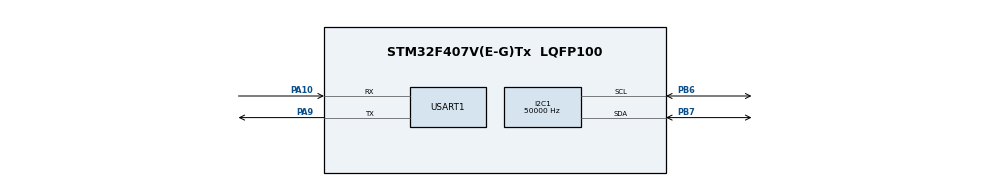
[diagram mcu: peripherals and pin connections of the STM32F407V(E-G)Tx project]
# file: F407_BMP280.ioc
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I2C1.ClockSpeed=50000
I2C1.I2C_Mode=I2C_Fast
Mcu.Family=STM32F4
Mcu.Name=STM32F407V(E-G)Tx
Mcu.Package=LQFP100
NVIC.I2C1_ER_IRQn=true\:0\:0\:false\:false\:true\:true\:true\:true
NVIC.I2C1_EV_IRQn=true\:0\:0\:false\:false\:true\:true\:true\:true
NVIC.PriorityGroup=NVIC_PRIORITYGROUP_4
NVIC.USART1_IRQn=true\:0\:0\:false\:false\:true\:true\:true\:true
PA10.Mode=Asynchronous
PA10.Signal=USART1_RX
PA9.Mode=Asynchronous
PA9.Signal=USART1_TX
PB6.Mode=I2C
PB6.Signal=I2C1_SCL
PB7.Mode=I2C
PB7.Signal=I2C1_SDA
PH0-OSC_IN.Mode=HSE-External-Oscillator
PH0-OSC_IN.Signal=RCC_OSC_IN
PH1-OSC_OUT.Mode=HSE-External-Oscillator
PH1-OSC_OUT.Signal=RCC_OSC_OUT
ProjectManager.HeapSize=0x200
ProjectManager.StackSize=0x400
ProjectManager.TargetToolchain=STM32CubeIDE
RCC.48MHZClocksFreq_Value=36000000
RCC.AHBFreq_Value=72000000
RCC.APB1CLKDivider=RCC_HCLK_DIV2
RCC.APB1Freq_Value=36000000
RCC.APB1TimFreq_Value=72000000
RCC.APB2Freq_Value=72000000
RCC.APB2TimFreq_Value=72000000
RCC.CortexFreq_Value=72000000
RCC.HCLKFreq_Value=72000000
RCC.HSE_VALUE=8000000
RCC.HSI_VALUE=16000000
RCC.LSE_VALUE=32768
RCC.PLLM=8
RCC.PLLN=72
RCC.SYSCLKFreq_VALUE=72000000
RCC.SYSCLKSource=RCC_SYSCLKSOURCE_PLLCLK
RCC.VCOOutputFreq_Value=144000000
USART1.VirtualMode=VM_ASYNC
board=custom

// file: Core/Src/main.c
/* USER CODE BEGIN Header */
/**
  ******************************************************************************
  * @file           : main.c
  * @brief          : Main program body
  ******************************************************************************
  * @attention
  *
  * Copyright (c) 2024 STMicroelectronics.
  * All rights reserved.
  *
  * This software is licensed under terms that can be found in the LICENSE file
  * in the root directory of this software component.
  * If no LICENSE file comes with this software, it is provided AS-IS.
  *
  ******************************************************************************
  */
/* USER CODE END Header */
#include "main.h"
#include "i2c.h"
#include "usart.h"
#include "gpio.h"

/* USER CODE BEGIN Includes */
#include "BMP280.h"
#include <stdio.h>
#include <string.h>
/* USER CODE END Includes */

void SystemClock_Config(void);

int main(void)
{

  /* MCU Configuration--------------------------------------------------------*/

  /* Reset of all peripherals, Initializes the Flash interface and the Systick. */
  HAL_Init();

  /* Configure the system clock */
  SystemClock_Config();

  /* Initialize all configured peripherals */
  MX_GPIO_Init();
  MX_I2C1_Init();
  MX_USART1_UART_Init();
  /* USER CODE BEGIN 2 */
  char message[20];
  float Temperture, Humidity;

  BMP280_Init();
  HAL_Delay(50);
  BMP280_ReadReg(&Temperture, &Humidity);
  /* USER CODE END 2 */

  /* Infinite loop */
  /* USER CODE BEGIN WHILE */
  while (1)
  {
	  sprintf(message, "温度: %.lf ℃, 湿度: %.lf %%\r\n", Temperture, Humidity);
	  HAL_UART_Transmit(&huart1, message, strlen(message), HAL_MAX_DELAY);

	  HAL_Delay(500);
    /* USER CODE END WHILE */

  }
}

void SystemClock_Config(void)
{
  RCC_OscInitTypeDef RCC_OscInitStruct = {0};
  RCC_ClkInitTypeDef RCC_ClkInitStruct = {0};

  /** Configure the main internal regulator output voltage
  */
  __HAL_RCC_PWR_CLK_ENABLE();
  __HAL_PWR_VOLTAGESCALING_CONFIG(PWR_REGULATOR_VOLTAGE_SCALE1);

  /** Initializes the RCC Oscillators according to the specified parameters
  * in the RCC_OscInitTypeDef structure.
  */
  RCC_OscInitStruct.OscillatorType = RCC_OSCILLATORTYPE_HSI;
  RCC_OscInitStruct.HSIState = RCC_HSI_ON;
  RCC_OscInitStruct.HSICalibrationValue = RCC_HSICALIBRATION_DEFAULT;
  RCC_OscInitStruct.PLL.PLLState = RCC_PLL_NONE;
  if (HAL_RCC_OscConfig(&RCC_OscInitStruct) != HAL_OK)
  {
    Error_Handler();
  }

  /** Initializes the CPU, AHB and APB buses clocks
  */
  RCC_ClkInitStruct.ClockType = RCC_CLOCKTYPE_HCLK|RCC_CLOCKTYPE_SYSCLK
                              |RCC_CLOCKTYPE_PCLK1|RCC_CLOCKTYPE_PCLK2;
  RCC_ClkInitStruct.SYSCLKSource = RCC_SYSCLKSOURCE_HSI;
  RCC_ClkInitStruct.AHBCLKDivider = RCC_SYSCLK_DIV1;
  RCC_ClkInitStruct.APB1CLKDivider = RCC_HCLK_DIV1;
  RCC_ClkInitStruct.APB2CLKDivider = RCC_HCLK_DIV1;

  if (HAL_RCC_ClockConfig(&RCC_ClkInitStruct, FLASH_LATENCY_0) != HAL_OK)
  {
    Error_Handler();
  }
}

void Error_Handler(void)
{
  __disable_irq();
  while (1)
  {
  }
}
